VERSION 5.8 ;
BUSBITCHARS "<>" ;
DIVIDERCHAR "/" ;

UNITS
   DATABASE MICRONS 1000 ;
END UNITS

PROPERTYDEFINITIONS
   LAYER lip INTEGER ;
   LAYER lrp REAL ;
   LAYER lsp STRING ;
   VIA vip INTEGER RANGE 0 100 ;
   MACRO mrp REAL ;
   PIN psp STRING ;
END PROPERTYDEFINITIONS

LAYER M1
   TYPE ROUTING ;
   DIRECTION HORIZONTAL ;
   WIDTH 0.2 ;
   PITCH 0.4 ;
   OFFSET 0.1 ;
   SPACING 0.2 ;
   SPACING 0.16 SAMENET PGONLY ;
   SPACING 0.17 LENGTHTHRESHOLD 0.4 ;
   SPACING 0.18 RANGE 0.1 0.3 ;
   SPACING 0.19 RANGE 0.1 0.3 INFLUENCE 0.05 RANGE 0.2 0.4 ;
   RESISTANCE RPERSQ 0.5 ;
   CAPACITANCE CPERSQDIST 0.01 ;
   HEIGHT 1.0 ;
   THICKNESS 0.05 ;
   WIREEXTENSION 0.3 ;
   AREA 0.5 ;
   ANTENNALENGTHFACTOR 2.0 ;
   MINIMUMCUT 2 WIDTH 1.0 ;
   MINIMUMCUT 3 WIDTH 1.5 WITHIN 0.25 FROMABOVE LENGTH 2.0 WITHIN 0.5 ;
   MINSTEP 0.05 ;
   MINSTEP 0.05 INSIDECORNER LENGTHSUM 0.15 ;
   MINSTEP 1.0 MAXEDGES 2 ;
   SPACINGTABLE
      PARALLELRUNLENGTH 0.00 0.50 1.00
         WIDTH 0.00      0.20 0.25 0.30
         WIDTH 0.20      0.25 0.30 0.35 ;
   SPACINGTABLE
      INFLUENCE
         WIDTH 1.5 WITHIN 0.5 SPACING 0.5
         WIDTH 3.0 WITHIN 1.0 SPACING 1.0 ;
   PROPERTY lsp "top" ;
END M1

LAYER V1
   TYPE CUT ;
   WIDTH 0.15 ;
   SPACING 0.2 ;
   SPACING 0.22 ADJACENTCUTS 3 WITHIN 0.25 ;
   SPACING 0.23 ADJACENTCUTS 2 WITHIN 0.3 EXCEPTSAMEPGNET ;
   SPACING 0.6 LAYER M1 ;
   SPACING 1.5 PARALLELOVERLAP ;
   SPACING 0.24 CENTERTOCENTER ;
   SPACING 0.25 SAMENET ;
   SPACINGTABLE ORTHOGONAL
      WITHIN 0.15 SPACING 0.11
      WITHIN 0.13 SPACING 0.13 ;
   PROPERTY lip 5 ;
   PROPERTY lrp 2.3 ;
END V1

VIA VIA1
   RESISTANCE 1.5 ;
   PROPERTY vip 42 ;
   LAYER M1 ;
      RECT -1 -1 1 1 ;
   LAYER V1 ;
      RECT -0.5 -0.5 0.5 0.5 ;
END VIA1

VIARULE VIARULE1 GENERATE
   LAYER M1 ;
      ENCLOSURE 0.1 0.15 ;
      WIDTH 0.1 TO 1.9 ;
   LAYER M1 ;
      ENCLOSURE 0.1 0.15 ;
      WIDTH 0.1 TO 1.9 ;
   LAYER V1 ;
      RECT -0.1 -0.1 0.1 0.1 ;
      SPACING 0.5 BY 0.5 ;
      RESISTANCE 0.2 ;
END VIARULE1

NONDEFAULTRULE WIDE_M1
   HARDSPACING ;
   LAYER M1
      WIDTH 0.3 ;
      SPACING 0.25 ;
      WIREEXTENSION 0.1 ;
   END M1
   VIA ND_VIA1
      RESISTANCE 0.3 ;
      PROPERTY vip 7 ;
      LAYER M1 ;
         RECT -1 -1 1 1 ;
      LAYER V1 ;
         RECT -0.5 -0.5 0.5 0.5 ;
   END ND_VIA1
   USEVIA VIA1 ;
   MINCUTS V1 2 ;
END WIDE_M1

SITE CORE
   CLASS CORE ;
   SIZE 0.2 BY 2.0 ;
   SYMMETRY Y ;
END CORE

SITE DBLCORE
   CLASS CORE ;
   SIZE 0.4 BY 2.0 ;
   SYMMETRY X Y ;
   ROWPATTERN CORE N CORE FS ;
END DBLCORE

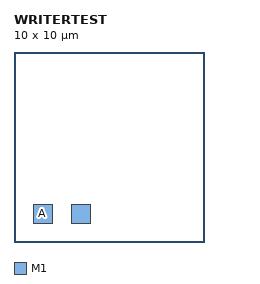
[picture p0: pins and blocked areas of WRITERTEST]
MACRO WRITERTEST
   CLASS CORE ;
   EEQ WRITERTEST ;
   FIXEDMASK ;
   ORIGIN 0 0 ;
   SIZE 10 BY 10 ;
   SYMMETRY X Y ;
   SITE CORE ;
   PROPERTY mrp 1.5 ;

   PIN A
      DIRECTION INPUT ;
      USE SIGNAL ;
      SHAPE ABUTMENT ;
      MUSTJOIN A ;
      NETEXPR "A (A1 A2)" ;
      PROPERTY psp "signal" ;
      PORT
         LAYER M1 ;
            RECT MASK 1 1 1 2 2 ;
            POLYGON 3 1 4 1 4 2 3 2 ;
            WIDTH 0.1 ;
            PATH 5 5 6 5 ;
      END
   END A

   OBS
      LAYER M1 ;
         RECT ITERATE 0 0 1 1
            DO 2 BY 2 STEP 3 3 ;
         WIDTH 0.1 ;
         PATH ITERATE 7 7 8 7
            DO 1 BY 2 STEP 0 3 ;
   END
END WRITERTEST
